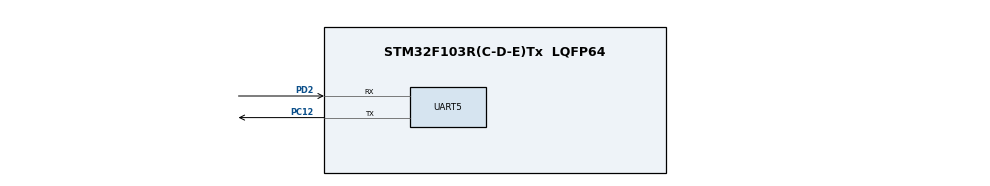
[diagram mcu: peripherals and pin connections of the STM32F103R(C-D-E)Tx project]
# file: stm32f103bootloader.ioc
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Mcu.Family=STM32F1
Mcu.Name=STM32F103R(C-D-E)Tx
Mcu.Package=LQFP64
NVIC.PriorityGroup=NVIC_PRIORITYGROUP_4
NVIC.TIM5_IRQn=true\:15\:0\:false\:false\:true\:false\:true
NVIC.TimeBase=TIM5_IRQn
NVIC.TimeBaseIP=TIM5
NVIC.UART5_IRQn=true\:0\:0\:false\:false\:true\:true\:true
PA13.Mode=Serial_Wire
PA13.Signal=SYS_JTMS-SWDIO
PA14.Mode=Serial_Wire
PA14.Signal=SYS_JTCK-SWCLK
PC12.Mode=Asynchronous
PC12.Signal=UART5_TX
PD0-OSC_IN.Mode=HSE-External-Oscillator
PD0-OSC_IN.Signal=RCC_OSC_IN
PD1-OSC_OUT.Mode=HSE-External-Oscillator
PD1-OSC_OUT.Signal=RCC_OSC_OUT
PD2.Mode=Asynchronous
PD2.Signal=UART5_RX
ProjectManager.HeapSize=0x200
ProjectManager.StackSize=0x400
ProjectManager.TargetToolchain=Makefile
RCC.AHBFreq_Value=72000000
RCC.APB1CLKDivider=RCC_HCLK_DIV2
RCC.APB1Freq_Value=36000000
RCC.APB1TimFreq_Value=72000000
RCC.APB2Freq_Value=72000000
RCC.APB2TimFreq_Value=72000000
RCC.HCLKFreq_Value=72000000
RCC.HSE_VALUE=12000000
RCC.PLLMUL=RCC_PLL_MUL6
RCC.PLLSourceVirtual=RCC_PLLSOURCE_HSE
RCC.SYSCLKFreq_VALUE=72000000
RCC.SYSCLKSource=RCC_SYSCLKSOURCE_PLLCLK
RCC.USBFreq_Value=72000000
UART5.VirtualMode=Asynchronous
VP_CRC_VS_CRC.Mode=CRC_Activate
VP_SYS_VS_tim5.Mode=TIM5
board=custom

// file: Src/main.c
/* USER CODE BEGIN Header */
/**
 ******************************************************************************
 * @file           : main.c
 * @brief          : Main program body
 ******************************************************************************
 * @attention
 *
 * <h2><center>&copy; Copyright (c) 2021 STMicroelectronics.
 * All rights reserved.</center></h2>
 *
 * This software component is licensed by ST under BSD 3-Clause license,
 * the "License"; You may not use this file except in compliance with the
 * License. You may obtain a copy of the License at:
 *                        opensource.org/licenses/BSD-3-Clause
 *
 ******************************************************************************
 */
/* USER CODE END Header */
#include "main.h"

/* USER CODE BEGIN Includes */
#include <stdio.h>
#include <errno.h>
#include <sys/unistd.h>
#include <fota_port.h>
/* USER CODE END Includes */

CRC_HandleTypeDef hcrc;

UART_HandleTypeDef huart5;

void SystemClock_Config(void);
static void MX_GPIO_Init(void);
static void MX_CRC_Init(void);
static void MX_UART5_Init(void);

/* USER CODE BEGIN 0 */
int _write(int file, char *data, int len) {
    HAL_StatusTypeDef status;
    if ((file != STDOUT_FILENO) && (file != STDERR_FILENO)) {
        errno = EBADF;
        return -1;
    }

    status = HAL_UART_Transmit(&FOTA_YMODEM_HUART, (uint8_t *) data, len, 1000);
    return (status == HAL_OK ? len : 0);
}
/* USER CODE END 0 */

int main(void)
{

  /* MCU Configuration--------------------------------------------------------*/

  /* Reset of all peripherals, Initializes the Flash interface and the Systick. */
  HAL_Init();

  /* Configure the system clock */
  SystemClock_Config();

  /* Initialize all configured peripherals */
  MX_GPIO_Init();
  MX_CRC_Init();
  MX_UART5_Init();
  /* USER CODE BEGIN 2 */
    printf("\r\n------START------\r\n");
  /* USER CODE END 2 */

  /* Infinite loop */
    while (1) {

    /* USER CODE BEGIN 3 */
        extern void fota_init(void);
        fota_init();
        HAL_Delay(1000);
    }
  /* USER CODE END 3 */
}

void SystemClock_Config(void)
{
  RCC_OscInitTypeDef RCC_OscInitStruct = {0};
  RCC_ClkInitTypeDef RCC_ClkInitStruct = {0};

  /** Initializes the RCC Oscillators according to the specified parameters
  * in the RCC_OscInitTypeDef structure.
  */
  RCC_OscInitStruct.OscillatorType = RCC_OSCILLATORTYPE_HSE;
  RCC_OscInitStruct.HSEState = RCC_HSE_ON;
  RCC_OscInitStruct.HSEPredivValue = RCC_HSE_PREDIV_DIV1;
  RCC_OscInitStruct.HSIState = RCC_HSI_ON;
  RCC_OscInitStruct.PLL.PLLState = RCC_PLL_ON;
  RCC_OscInitStruct.PLL.PLLSource = RCC_PLLSOURCE_HSE;
  RCC_OscInitStruct.PLL.PLLMUL = RCC_PLL_MUL10;
  if (HAL_RCC_OscConfig(&RCC_OscInitStruct) != HAL_OK)
  {
    Error_Handler();
  }
  /** Initializes the CPU, AHB and APB buses clocks
  */
  RCC_ClkInitStruct.ClockType = RCC_CLOCKTYPE_HCLK|RCC_CLOCKTYPE_SYSCLK
                              |RCC_CLOCKTYPE_PCLK1|RCC_CLOCKTYPE_PCLK2;
  RCC_ClkInitStruct.SYSCLKSource = RCC_SYSCLKSOURCE_PLLCLK;
  RCC_ClkInitStruct.AHBCLKDivider = RCC_SYSCLK_DIV1;
  RCC_ClkInitStruct.APB1CLKDivider = RCC_HCLK_DIV2;
  RCC_ClkInitStruct.APB2CLKDivider = RCC_HCLK_DIV1;

  if (HAL_RCC_ClockConfig(&RCC_ClkInitStruct, FLASH_LATENCY_2) != HAL_OK)
  {
    Error_Handler();
  }
}

static void MX_CRC_Init(void)
{

  hcrc.Instance = CRC;
  if (HAL_CRC_Init(&hcrc) != HAL_OK)
  {
    Error_Handler();
  }

}

static void MX_UART5_Init(void)
{

  huart5.Instance = UART5;
  huart5.Init.BaudRate = 115200;
  huart5.Init.WordLength = UART_WORDLENGTH_8B;
  huart5.Init.StopBits = UART_STOPBITS_1;
  huart5.Init.Parity = UART_PARITY_NONE;
  huart5.Init.Mode = UART_MODE_TX_RX;
  huart5.Init.HwFlowCtl = UART_HWCONTROL_NONE;
  huart5.Init.OverSampling = UART_OVERSAMPLING_16;
  if (HAL_UART_Init(&huart5) != HAL_OK)
  {
    Error_Handler();
  }

}

static void MX_GPIO_Init(void)
{

  /* GPIO Ports Clock Enable */
  __HAL_RCC_GPIOD_CLK_ENABLE();
  __HAL_RCC_GPIOA_CLK_ENABLE();
  __HAL_RCC_GPIOC_CLK_ENABLE();

}

void HAL_TIM_PeriodElapsedCallback(TIM_HandleTypeDef *htim)
{
  if (htim->Instance == TIM5) {
    HAL_IncTick();
  }
}

void Error_Handler(void)
{
  /* USER CODE BEGIN Error_Handler_Debug */
    /* User can add his own implementation to report the HAL error return state
     */
    __disable_irq();
    while (1) {}
  /* USER CODE END Error_Handler_Debug */
}

#ifdef  USE_FULL_ASSERT
/**
  * @brief  Reports the name of the source file and the source line number
  *         where the assert_param error has occurred.
  * @param  file: pointer to the source file name
  * @param  line: assert_param error line source number
  * @retval None
  */
void assert_failed(uint8_t *file, uint32_t line)
{
  /* USER CODE BEGIN 6 */
    /* User can add his own implementation to report the file name and line
       number, ex: printf("Wrong parameters value: file %s on line %d\r\n",
       file, line) */
  /* USER CODE END 6 */
}
#endif /* USE_FULL_ASSERT */

/************************ (C) COPYRIGHT STMicroelectronics *****END OF FILE****/
